VERSION 5.8 ;
BUSBITCHARS "[]" ;
DIVIDERCHAR "/" ;
UNITS
  DATABASE MICRONS 1000 ;
END UNITS
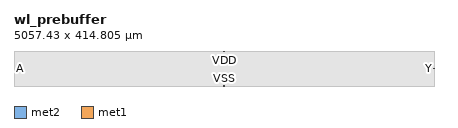
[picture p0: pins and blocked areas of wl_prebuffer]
MACRO wl_prebuffer
  CLASS BLOCK ;
  ORIGIN 0 0 ;
  FOREIGN wl_prebuffer 0 0 ;
  SIZE 5057.43 BY 414.805 ;
  SYMMETRY X Y ;
  PIN A
    DIRECTION INPUT ;
    USE SIGNAL ;
    PORT
      LAYER met2 ;
        RECT 0 204.9 5 209.9 ;
    END
  END A
  PIN Y
    DIRECTION OUTPUT ;
    USE SIGNAL ;
    PORT
      LAYER met2 ;
        RECT 5052.43 204.9 5057.43 209.9 ;
    END
  END Y
  PIN VDD
    DIRECTION INOUT ;
    USE POWER ;
    PORT
      LAYER met1 ;
        RECT 2526.215 409.805 2531.215 414.805 ;
    END
  END VDD
  PIN VSS
    DIRECTION INOUT ;
    USE GROUND ;
    PORT
      LAYER met1 ;
        RECT 2526.215 0 2531.215 5 ;
    END
  END VSS
  OBS
    LAYER met1 ;
      RECT 0 0 5057.43 414.805 ;
  END
END wl_prebuffer
END LIBRARY
